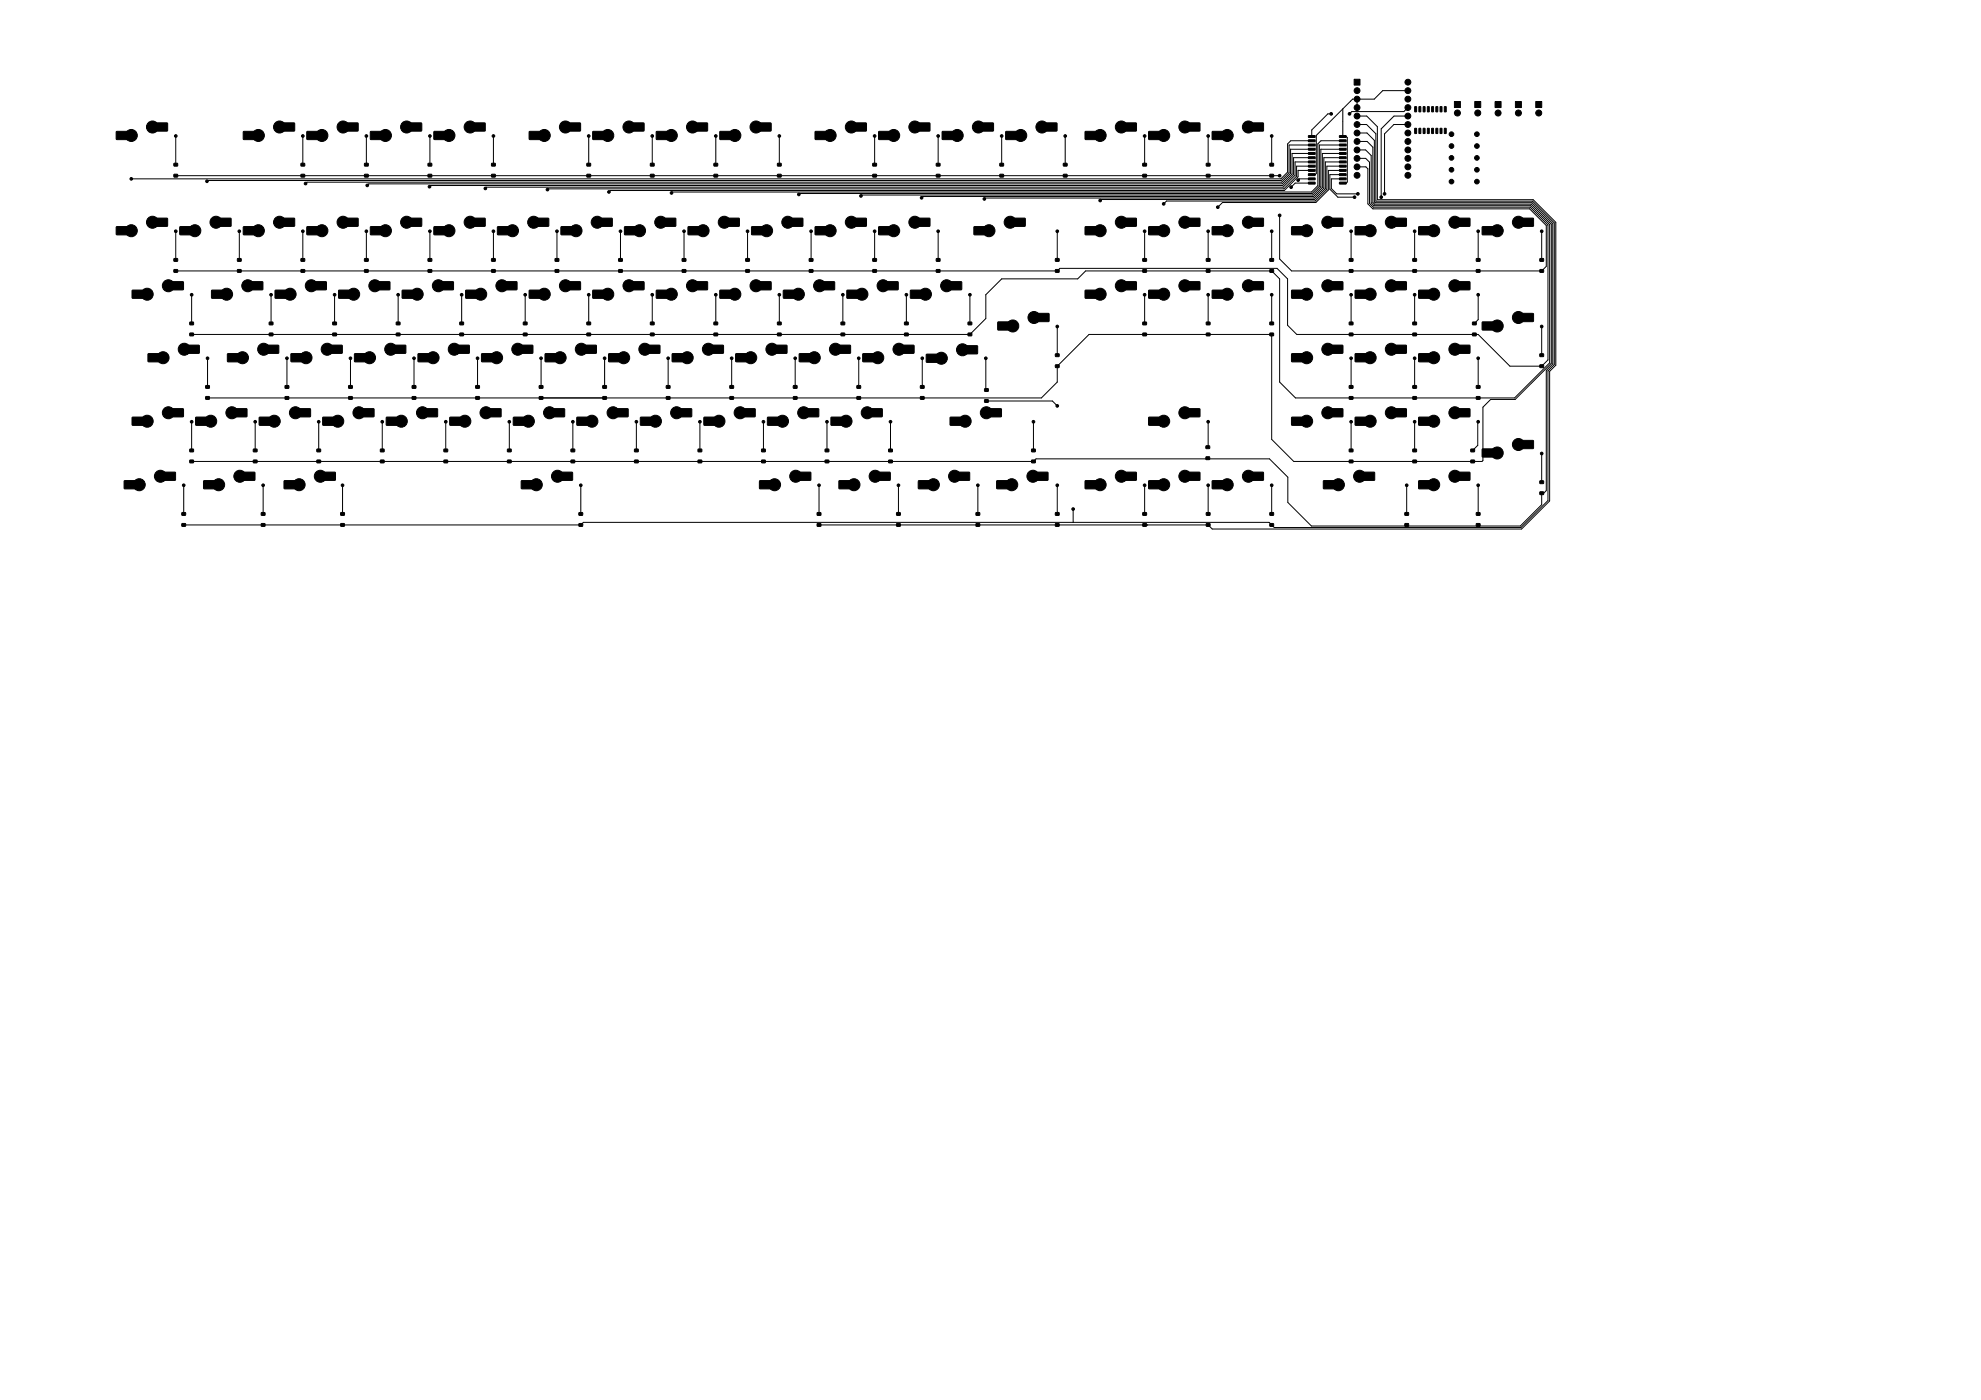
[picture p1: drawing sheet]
<svg xmlns="http://www.w3.org/2000/svg" width="594mm" height="420mm" viewBox="0 0 594 420" stroke-linecap="round" stroke-linejoin="round" font-family="sans-serif">
<g fill="#000" stroke="#000" stroke-width=".3">
<path d="M34.9 39.5h3.4v2.3h-3.4zM46.8 36.9h3.4v2.4h-3.4zM73 39.5h3.4v2.3h-3.4zM84.9 36.9h3.4v2.4h-3.4zM92 39.5h3.4v2.3h-3.4zM103.9 36.9h3.5v2.4h-3.5zM111.1 39.5h3.4v2.3h-3.4zM123 36.9h3.4v2.4h-3.4zM130.1 39.5h3.4v2.3h-3.4zM142 36.9h3.5v2.4h-3.5zM158.7 39.5h3.4v2.3h-3.4zM170.6 36.9h3.4v2.4h-3.4z"/>
<path d="M177.8 39.5h3.4v2.3h-3.4zM189.7 36.9h3.4v2.4h-3.4zM196.8 39.5h3.4v2.3h-3.4zM208.7 36.9h3.4v2.4h-3.4zM215.9 39.5h3.4v2.3h-3.4zM227.8 36.9h3.4v2.4h-3.4zM244.4 39.5h3.4v2.3h-3.4zM256.3 36.9h3.4l.1 2.3-3.4 .1zM263.5 39.5l3.3-.1 .2 2.3-3.4 .2zM275.4 36.9h3.3l.2 2.3-3.4 .1zM282.5 39.5l3.4-.1 .1 2.3-3.4 .2zM294.4 36.9h3.4l.1 2.3-3.4 .1z"/>
<path d="M301.6 39.5l3.3-.1 .2 2.3-3.4 .2zM313.5 36.9h3.3l.2 2.3-3.4 .1zM325.4 39.5l3.3-.1 .2 2.3-3.4 .2zM337.3 36.9h3.3l.2 2.3-3.4 .1zM344.5 39.5l3.3-.1 .1 2.3-3.4 .2zM356.4 36.9h3.3l.1 2.3-3.4 .1zM363.5 39.5l3.3-.1 .2 2.3-3.4 .2zM375.4 36.9h3.3l.2 2.3-3.4 .1zM406 23.8h1.8v1.7h-1.8zM424.2 32l.6 .1-.1 1.5-.5-.1zM424.2 38.5l.6 .1-.1 1.5-.5-.1zM425.5 32l.5 .1v1.5l-.5-.1z"/>
<path d="M425.5 38.5l.5 .1v1.5l-.5-.1zM426.8 32l.5 .1-.1 1.5-.5-.1zM426.8 38.5l.5 .1-.1 1.5-.5-.1zM428 32l.6 .1-.1 1.5-.5-.1zM428 38.5l.6 .1-.1 1.5-.5-.1zM429.3 32l.5 .1v1.5l-.5-.1zM429.3 38.5l.5 .1v1.5l-.5-.1zM430.6 32l.5 .1-.1 1.5-.5-.1zM430.6 38.5l.5 .1-.1 1.5-.5-.1zM431.8 32l.6 .1-.1 1.5-.5-.1zM431.8 38.5l.6 .1-.1 1.5-.5-.1zM433.1 32l.6 .1-.1 1.5-.5-.1z"/>
<path d="M433.1 38.5l.6 .1-.1 1.5-.5-.1zM436.1 30.5h1.8v1.8h-1.8zM442.2 30.5h1.8v1.8h-1.8zM448.3 30.5h1.8v1.8h-1.8zM454.4 30.5h1.8v1.8h-1.8zM460.5 30.5h1.8v1.8h-1.8zM52.2 52.3h1v.8h-1zM52.2 49h1v.8h-1zM90.3 52.3h1v.8h-1zM90.3 49h1v.8h-1zM109.3 52.3h1.1v.8h-1.1zM109.3 49h1.1v.8h-1.1z"/>
<path d="M128.4 52.3h1v.8h-1zM128.4 49h1v.8h-1zM147.4 52.3h1.1v.8h-1.1zM147.4 49h1.1v.8h-1.1zM176 52.3h1.1v.8h-1.1zM176 49h1.1v.8h-1.1zM195 52.3h1.1v.8h-1.1zM195 49h1.1v.8h-1.1zM214.1 52.3h1.1v.8h-1.1zM214.1 49h1.1v.8h-1.1zM233.1 52.3h1.1v.8h-1.1zM233.1 49h1.1v.8h-1.1z"/>
<path d="M261.7 52.3h1.1v.8h-1.1zM261.7 49h1.1v.8h-1.1zM280.8 52.3h1v.8h-1zM280.8 49h1v.8h-1zM299.8 52.3h1.1v.8h-1.1zM299.8 49h1.1v.8h-1.1zM318.9 52.3h1v.8h-1zM318.9 49h1v.8h-1zM342.7 52.3h1.1v.8h-1.1zM342.7 49h1.1v.8h-1.1zM361.7 52.3h1.1v.8h-1.1zM361.7 49h1.1v.8h-1.1z"/>
<path d="M380.8 52.3h1.1v.8h-1.1zM380.8 49h1.1v.8h-1.1zM392.4 54.7l1.9-.1 .1 .5-2 .1zM392.4 53.4h1.9l.1 .5h-2zM392.4 52.1h1.9l.1 .5-2 .1zM392.4 50.9l1.9-.1 .1 .5-2 .1zM392.4 49.6h1.9l.1 .5h-2zM392.4 48.3h1.9l.1 .5-2 .1zM392.4 47.1l1.9-.1 .1 .5-2 .1zM392.4 45.8l1.9-.1 .1 .5-2 .1zM392.4 44.5h1.9l.1 .5-2 .1zM392.4 43.2h1.9l.1 .5-2 .1z"/>
<path d="M392.4 42l1.9-.1 .1 .5-2 .1zM392.4 40.7h1.9l.1 .5h-2zM401.7 40.7h1.9v.5h-1.9zM401.7 42l1.9-.1v.5l-1.9 .1zM401.7 43.2h1.9v.5l-1.9 .1zM401.7 44.5h1.9v.5l-1.9 .1zM401.7 45.8l1.9-.1v.5l-1.9 .1zM401.7 47.1l1.9-.1v.5l-1.9 .1zM401.7 48.3h1.9v.5l-1.9 .1zM401.7 49.6h1.9v.5h-1.9zM401.7 50.9l1.9-.1v.5l-1.9 .1zM401.7 52.1h1.9v.5l-1.9 .1z"/>
<path d="M401.7 53.4h1.9v.5h-1.9zM401.7 54.7l1.9-.1v.5l-1.9 .1zM34.9 68h3.4v2.4h-3.4zM46.8 65.5h3.4v2.4h-3.4zM52.2 77.6h1v.8h-1zM53.9 68h3.4v2.4h-3.4zM65.8 65.5h3.5v2.4h-3.5zM71.2 77.6h1.1v.8h-1.1zM73 68h3.4v2.4h-3.4zM84.9 65.5h3.4v2.4h-3.4zM90.3 77.6h1v.8h-1zM92 68h3.4v2.4h-3.4z"/>
<path d="M103.9 65.5h3.5v2.4h-3.5zM109.3 77.6h1.1v.8h-1.1zM111.1 68h3.4v2.4h-3.4zM123 65.5h3.4v2.4h-3.4zM128.4 77.6h1v.8h-1zM130.1 68h3.4v2.4h-3.4zM142 65.5h3.5v2.4h-3.5zM147.4 77.6h1.1v.8h-1.1zM149.2 68h3.4v2.4h-3.4zM161.1 65.5h3.4v2.4h-3.4zM166.5 77.6h1v.8h-1zM168.2 68h3.4v2.4h-3.4z"/>
<path d="M180.1 65.5h3.5v2.4h-3.5zM185.5 77.6h1.1v.8h-1.1zM187.3 68h3.4v2.4h-3.4zM199.2 65.5h3.4v2.4h-3.4zM204.6 77.6h1v.8h-1zM206.3 68h3.4v2.4h-3.4zM218.2 65.5h3.5v2.4h-3.5zM223.6 77.6h1.1v.8h-1.1zM225.4 68h3.4v2.4h-3.4zM237.3 65.5h3.4v2.4h-3.4zM242.7 77.6h1v.8h-1zM244.4 68h3.4v2.4h-3.4z"/>
<path d="M256.3 65.5l3.4-.1 .1 2.4-3.4 .1zM261.7 77.6h1.1v.8h-1.1zM263.5 68h3.3l.2 2.3-3.4 .1zM275.4 65.5l3.3-.1 .2 2.4-3.4 .1zM280.8 77.6h1v.8h-1zM292.1 68h3.3l.1 2.3-3.4 .1zM304 65.5l3.3-.1 .1 2.4-3.3 .1zM316.5 77.6h1.1v.8h-1.1zM325.4 68h3.3l.2 2.3-3.4 .1zM337.3 65.5l3.3-.1 .2 2.4-3.4 .1zM342.7 77.6h1.1v.8h-1.1zM344.5 68h3.3l.1 2.3-3.4 .1z"/>
<path d="M356.4 65.5l3.3-.1 .1 2.4-3.4 .1zM361.7 77.6h1.1v.8h-1.1zM363.5 68h3.3l.2 2.3-3.4 .1zM375.4 65.5l3.3-.1 .2 2.4-3.4 .1zM380.8 77.6h1.1v.8h-1.1zM387.3 68h3.3l.2 2.3-3.4 .1zM399.2 65.5l3.3-.1 .2 2.4-3.4 .1zM404.6 77.6h1.1v.8h-1.1zM406.4 68h3.3l.1 2.3-3.4 .1zM418.3 65.5l3.3-.1 .1 2.4-3.3 .1zM423.6 77.6h1.1v.8h-1.1zM425.4 68h3.3l.2 2.3-3.4 .1z"/>
<path d="M437.3 65.5l3.3-.1 .2 2.4-3.4 .1zM442.7 77.6h1.1v.8h-1.1zM444.5 68h3.3l.1 2.3-3.4 .1zM456.4 65.5l3.3-.1 .1 2.4-3.3 .1zM461.7 77.6h1.1v.8h-1.1zM39.7 87.1h3.4v2.3h-3.4zM51.6 84.5h3.4v2.4h-3.4zM52.2 80.9h1v.8h-1zM56.9 96.6h1.1v.8h-1.1zM63.5 87.1h3.4v2.3h-3.4zM71.2 80.9h1.1v.8h-1.1zM75.4 84.5h3.4v2.4h-3.4z"/>
<path d="M80.7 96.6h1.1v.8h-1.1zM82.5 87.1h3.4v2.3h-3.4zM90.3 80.9h1v.8h-1zM94.4 84.5h3.4v2.4h-3.4zM99.8 96.6h1.1v.8h-1.1zM101.6 87.1h3.4v2.3h-3.4zM109.3 80.9h1.1v.8h-1.1zM113.5 84.5h3.4v2.4h-3.4zM118.8 96.6h1.1v.8h-1.1zM120.6 87.1h3.4v2.3h-3.4zM128.4 80.9h1v.8h-1zM132.5 84.5h3.4v2.4h-3.4z"/>
<path d="M137.9 96.6h1.1v.8h-1.1zM139.7 87.1h3.4v2.3h-3.4zM147.4 80.9h1.1v.8h-1.1zM151.6 84.5h3.4v2.4h-3.4zM156.9 96.6h1.1v.8h-1.1zM158.7 87.1h3.4v2.3h-3.4zM166.5 80.9h1v.8h-1zM170.6 84.5h3.4v2.4h-3.4zM176 96.6h1.1v.8h-1.1zM177.8 87.1h3.4v2.3h-3.4zM185.5 80.9h1.1v.8h-1.1zM189.7 84.5h3.4v2.4h-3.4z"/>
<path d="M195 96.6h1.1v.8h-1.1zM196.8 87.1h3.4v2.3h-3.4zM204.6 80.9h1v.8h-1zM208.7 84.5h3.4v2.4h-3.4zM214.1 96.6h1.1v.8h-1.1zM215.9 87.1h3.4v2.3h-3.4zM223.6 80.9h1.1v.8h-1.1zM227.8 84.5h3.4v2.4h-3.4zM233.1 96.6h1.1v.8h-1.1zM234.9 87.1h3.4v2.3h-3.4zM242.7 80.9h1v.8h-1zM246.8 84.5h3.4v2.4h-3.4z"/>
<path d="M252.2 96.6h1.1v.8h-1.1zM254 87.1l3.3-.1 .1 2.4-3.4 .1zM261.7 80.9h1.1v.8h-1.1zM265.9 84.5h3.3l.1 2.3-3.3 .2zM271.2 96.6h1.1v.8h-1.1zM273 87.1l3.3-.1 .2 2.4-3.4 .1zM280.8 80.9h1v.8h-1zM284.9 84.5h3.3l.2 2.3-3.4 .2zM290.3 96.6h1.1v.8h-1.1zM299.2 96.6h3.4v2.4h-3.4zM311.1 94.1h3.4v2.3h-3.4zM316.5 80.9h1.1v.8h-1.1z"/>
<path d="M325.4 87.1l3.3-.1 .2 2.4-3.4 .1zM337.3 84.5h3.3l.2 2.3-3.4 .2zM342.7 80.9h1.1v.8h-1.1zM342.7 96.6h1.1v.8h-1.1zM344.5 87.1l3.3-.1 .1 2.4-3.4 .1zM356.4 84.5h3.3l.1 2.3-3.4 .2zM361.7 80.9h1.1v.8h-1.1zM361.7 96.6h1.1v.8h-1.1zM363.5 87.1l3.3-.1 .2 2.4-3.4 .1zM375.4 84.5h3.3l.2 2.3-3.4 .2zM380.8 80.9h1.1v.8h-1.1zM380.8 96.6h1.1v.8h-1.1z"/>
<path d="M387.3 87.1l3.3-.1 .2 2.4-3.4 .1zM399.2 84.5h3.3l.2 2.3-3.4 .2zM404.6 96.6h1.1v.8h-1.1zM404.6 80.9h1.1v.8h-1.1zM406.4 87.1l3.3-.1 .1 2.4-3.4 .1zM418.3 84.5h3.3l.1 2.3-3.3 .2zM423.6 80.9h1.1v.8h-1.1zM423.6 96.6h1.1v.8h-1.1zM425.4 87.1l3.3-.1 .2 2.4-3.4 .1zM437.3 84.5h3.3l.2 2.3-3.4 .2zM441.6 96.6h1v.8h-1zM442.7 80.9h1.1v.8h-1.1z"/>
<path d="M444.5 96.6h3.3l.1 2.3-3.4 .1zM456.4 94.1l3.3-.1 .1 2.3-3.3 .2zM461.7 80.9h1.1v.8h-1.1zM44.4 106.1h3.4v2.4h-3.4zM56.3 103.6h3.4v2.4h-3.4zM56.9 99.9h1.1v.8h-1.1zM61.7 119h1.1v.8h-1.1zM61.7 115.7h1.1v.8h-1.1zM68.2 106.1h3.4v2.4h-3.4zM80.1 103.6h3.4v2.4h-3.4zM80.7 99.9h1.1v.8h-1.1zM85.5 119h1.1v.8h-1.1z"/>
<path d="M85.5 115.7h1.1v.8h-1.1zM87.3 106.1h3.4v2.4h-3.4zM99.2 103.6h3.4v2.4h-3.4zM99.8 99.9h1.1v.8h-1.1zM104.6 119h1v.8h-1zM104.6 115.7h1v.8h-1zM106.3 106.1h3.4v2.4h-3.4zM118.2 103.6h3.4v2.4h-3.4zM118.8 99.9h1.1v.8h-1.1zM123.6 119h1.1v.8h-1.1zM123.6 115.7h1.1v.8h-1.1zM125.4 106.1h3.4v2.4h-3.4z"/>
<path d="M137.3 103.6h3.4v2.4h-3.4zM137.9 99.9h1.1v.8h-1.1zM142.7 119h1v.8h-1zM142.7 115.7h1v.8h-1zM144.4 106.1h3.4v2.4h-3.4zM156.3 103.6h3.4v2.4h-3.4zM156.9 99.9h1.1v.8h-1.1zM161.7 119h1.1v.8h-1.1zM161.7 115.7h1.1v.8h-1.1zM163.5 106.1h3.4v2.4h-3.4zM175.4 103.6h3.4v2.4h-3.4zM176 99.9h1.1v.8h-1.1z"/>
<path d="M180.8 119h1v.8h-1zM180.8 115.7h1v.8h-1zM182.5 106.1h3.4v2.4h-3.4zM194.4 103.6h3.4v2.4h-3.4zM195 99.9h1.1v.8h-1.1zM199.8 119h1.1v.8h-1.1zM199.8 115.7h1.1v.8h-1.1zM201.6 106.1h3.4v2.4h-3.4zM213.5 103.6h3.4v2.4h-3.4zM214.1 99.9h1.1v.8h-1.1zM218.9 119h1v.8h-1zM218.9 115.7h1v.8h-1z"/>
<path d="M220.6 106.1h3.4v2.4h-3.4zM232.5 103.6h3.4v2.4h-3.4zM233.1 99.9h1.1v.8h-1.1zM237.9 119h1.1v.8h-1.1zM237.9 115.7h1.1v.8h-1.1zM239.7 106.1h3.4v2.4h-3.4zM251.6 103.6l3.3-.1 .1 2.4-3.3 .1zM252.2 99.9h1.1v.8h-1.1zM257 119h1v.8h-1zM257 115.7h1v.8h-1zM258.7 106.1h3.4l.1 2.3-3.4 .1zM270.6 103.6l3.4-.1 .1 2.4-3.4 .1z"/>
<path d="M271.2 99.9h1.1v.8h-1.1zM276 119h1.1v.8h-1.1zM276 115.7h1.1v.8h-1.1zM277.8 106.3l3.3-.1 .1 2.4-3.4 .1zM289.7 103.8l3.3-.1 .1 2.3-3.4 .1zM290.3 99.9h1.1v.8h-1.1zM295.2 116.6h1.1v.8h-1.1zM316.5 109.5h1.1v.7h-1.1zM316.5 106.2h1.1v.7h-1.1zM342.7 99.9h1.1v.8h-1.1zM361.7 99.9h1.1v.8h-1.1zM380.8 99.9h1.1v.8h-1.1z"/>
<path d="M387.3 106.1h3.3l.2 2.3-3.4 .1zM399.2 103.6l3.3-.1 .2 2.4-3.4 .1zM404.6 99.9h1.1v.8h-1.1zM404.6 119h1.1v.8h-1.1zM404.6 115.7h1.1v.8h-1.1zM406.4 106.1h3.3l.1 2.3-3.4 .1zM418.3 103.6l3.3-.1 .1 2.4-3.3 .1zM423.6 119h1.1v.8h-1.1zM423.6 115.7h1.1v.8h-1.1zM423.6 99.9h1.1v.8h-1.1zM425.4 106.1h3.3l.2 2.3-3.4 .1zM437.3 103.6l3.3-.1 .2 2.4-3.4 .1z"/>
<path d="M441.6 99.9h1v.8h-1zM442.7 119h1.1v.8h-1.1zM442.7 115.7h1.1v.8h-1.1zM461.7 109.5h1.1v.7h-1.1zM461.7 106.2h1.1v.7h-1.1zM39.7 125.2h3.4v2.3h-3.4zM51.6 122.6h3.4v2.4h-3.4zM56.9 138h1.1v.8h-1.1zM56.9 134.7h1.1v.8h-1.1zM58.7 125.2h3.4v2.3h-3.4zM70.6 122.6h3.4v2.4h-3.4zM76 138h1.1v.8h-1.1z"/>
<path d="M76 134.7h1.1v.8h-1.1zM77.8 125.2h3.4v2.3h-3.4zM89.7 122.6h3.4v2.4h-3.4zM95 138h1.1v.8h-1.1zM95 134.7h1.1v.8h-1.1zM96.8 125.2h3.4v2.3h-3.4zM108.7 122.6h3.4v2.4h-3.4zM114.1 138h1.1v.8h-1.1zM114.1 134.7h1.1v.8h-1.1zM115.9 125.2h3.4v2.3h-3.4zM127.8 122.6h3.4v2.4h-3.4zM133.1 138h1.1v.8h-1.1z"/>
<path d="M133.1 134.7h1.1v.8h-1.1zM134.9 125.2h3.4v2.3h-3.4zM146.8 122.6h3.4v2.4h-3.4zM152.2 138h1.1v.8h-1.1zM152.2 134.7h1.1v.8h-1.1zM154 125.2h3.4v2.3h-3.4zM165.9 122.6h3.4v2.4h-3.4zM171.2 138h1.1v.8h-1.1zM171.2 134.7h1.1v.8h-1.1zM173 125.2h3.4v2.3h-3.4zM184.9 122.6h3.4v2.4h-3.4zM190.3 138h1.1v.8h-1.1z"/>
<path d="M190.3 134.7h1.1v.8h-1.1zM192.1 125.2h3.4v2.3h-3.4zM204 122.6h3.4v2.4h-3.4zM209.3 138h1.1v.8h-1.1zM209.3 134.7h1.1v.8h-1.1zM211.1 125.2h3.4v2.3h-3.4zM223 122.6h3.4v2.4h-3.4zM228.4 138h1.1v.8h-1.1zM228.4 134.7h1.1v.8h-1.1zM230.2 125.2h3.4v2.3h-3.4zM242.1 122.6h3.4v2.4h-3.4zM247.4 138h1.1v.8h-1.1z"/>
<path d="M247.4 134.7h1.1v.8h-1.1zM249.2 125.2h3.4v2.3h-3.4zM261.1 122.6h3.3l.2 2.3-3.4 .2zM266.5 138h1.1v.8h-1.1zM266.5 134.7h1.1v.8h-1.1zM284.9 125.2h3.4v2.3h-3.4zM295.2 119.9h1.1v.8h-1.1zM296.8 122.6h3.4v2.4h-3.4zM309.3 138h1.1v.8h-1.1zM309.3 134.7h1.1v.8h-1.1zM344.5 125.2l3.3-.1 .1 2.4-3.4 .1zM356.4 122.6h3.3l.1 2.3-3.4 .2z"/>
<path d="M361.6 137.1l1-.1 .1 .8-1 .1zM361.6 133.8h1.1v.7h-1.1zM387.3 125.2l3.3-.1 .2 2.4-3.4 .1zM399.2 122.6h3.3l.2 2.3-3.4 .2zM404.6 138h1.1v.8h-1.1zM404.6 134.7h1.1v.8h-1.1zM406.4 125.2l3.3-.1 .1 2.4-3.4 .1zM418.3 122.6h3.3l.1 2.3-3.3 .2zM423.6 138h1.1v.8h-1.1zM423.6 134.7h1.1v.8h-1.1zM425.4 125.2l3.3-.1 .2 2.4-3.4 .1zM437.3 122.6h3.3l.2 2.3-3.4 .2z"/>
<path d="M441 138h1.1v.8h-1.1zM441 134.7h1.1v.8h-1.1zM444.5 134.7h3.3l.1 2.3-3.4 .1zM456.4 132.2l3.3-.1 .1 2.3-3.3 .2zM37.3 144.2h3.4v2.4h-3.4zM49.2 141.7h3.4v2.4h-3.4zM54.6 157.1h1v.8h-1zM54.6 153.8h1v.8h-1zM61.1 144.2h3.4v2.4h-3.4zM73 141.7h3.4v2.4h-3.4zM78.4 157.1h1v.8h-1zM78.4 153.8h1v.8h-1z"/>
<path d="M85.2 144.2h3.4v2.4h-3.4zM97.1 141.7h3.4v2.4h-3.4zM102.2 157.1h1v.8h-1zM102.2 153.8h1v.8h-1zM156.3 144.2h3.4v2.4h-3.4zM168.2 141.7h3.4v2.4h-3.4zM173.6 157.1h1.1v.8h-1.1zM173.6 153.8h1.1v.8h-1.1zM227.8 144.2h3.4v2.4h-3.4zM239.7 141.7h3.4v2.4h-3.4zM245.1 157.1h1v.8h-1zM245.1 153.8h1v.8h-1z"/>
<path d="M251.6 144.2h3.4v2.4h-3.4zM263.5 141.7h3.4v2.4h-3.4zM268.9 157.1h1v.8h-1zM268.9 153.8h1v.8h-1zM275.4 144.2h3.4v2.4h-3.4zM287.3 141.7h3.4v2.4h-3.4zM292.7 157.1h1v.8h-1zM292.7 153.8h1v.8h-1zM298.9 144.2h3.4v2.4h-3.4zM310.8 141.7h3.4v2.4h-3.4zM316.5 157.1h1.1v.8h-1.1zM316.5 153.8h1.1v.8h-1.1z"/>
<path d="M325.4 144.2h3.3l.2 2.3-3.4 .1zM337.3 141.7l3.3-.1 .2 2.4-3.4 .1zM342.7 157.1h1.1v.8h-1.1zM342.7 153.8h1.1v.8h-1.1zM344.5 144.2h3.3l.1 2.3-3.4 .1zM356.4 141.7l3.3-.1 .1 2.4-3.4 .1zM361.7 157.1h1.1v.8h-1.1zM361.7 153.8h1.1v.8h-1.1zM363.5 144.2h3.3l.2 2.3-3.4 .1zM375.4 141.7l3.3-.1 .2 2.4-3.4 .1zM380.8 157.1h1.1v.8h-1.1zM380.8 153.8h1.1v.8h-1.1z"/>
<path d="M396.8 144.2h3.4l.1 2.3-3.4 .1zM408.7 141.7l3.4-.1 .1 2.4-3.4 .1zM421.3 157.1h1v.8h-1zM421.3 153.8h1v.8h-1zM425.4 144.2h3.3l.2 2.3-3.4 .1zM437.3 141.7l3.3-.1 .2 2.4-3.4 .1zM442.7 157.1h1.1v.8h-1.1zM442.7 153.8h1.1v.8h-1.1zM461.7 147.6h1.1v.7h-1.1zM461.7 144.3h1.1v.7h-1.1z"/>
<circle cx="45.7" cy="38.1" r="1.8"/>
<circle cx="83.8" cy="38.1" r="1.8"/>
<circle cx="102.9" cy="38.1" r="1.8"/>
<circle cx="121.9" cy="38.1" r="1.8"/>
<circle cx="141" cy="38.1" r="1.8"/>
<circle cx="169.5" cy="38.1" r="1.8"/>
<circle cx="188.6" cy="38.1" r="1.8"/>
<circle cx="207.6" cy="38.1" r="1.8"/>
<circle cx="226.7" cy="38.1" r="1.8"/>
<circle cx="255.3" cy="38.1" r="1.8"/>
<circle cx="274.3" cy="38.1" r="1.8"/>
<circle cx="293.4" cy="38.1" r="1.8"/>
<circle cx="312.4" cy="38.1" r="1.8"/>
<circle cx="336.2" cy="38.1" r="1.8"/>
<circle cx="355.3" cy="38.1" r="1.8"/>
<circle cx="374.3" cy="38.1" r="1.8"/>
<circle cx="399.2" cy="34.2" r=".4"/>
<circle cx="404.7" cy="34.2" r=".4"/>
<circle cx="406.9" cy="39.9" r=".88"/>
<circle cx="406.9" cy="34.8" r=".88"/>
<circle cx="406.9" cy="27.2" r=".88"/>
<circle cx="406.9" cy="29.7" r=".88"/>
<circle cx="406.9" cy="32.3" r=".88"/>
<circle cx="406.9" cy="37.4" r=".88"/>
<circle cx="422.2" cy="32.3" r=".88"/>
<circle cx="422.2" cy="27.2" r=".88"/>
<circle cx="422.2" cy="39.9" r=".88"/>
<circle cx="422.2" cy="37.4" r=".88"/>
<circle cx="422.2" cy="24.7" r=".88"/>
<circle cx="422.2" cy="34.8" r=".88"/>
<circle cx="422.2" cy="29.7" r=".88"/>
<circle cx="437" cy="33.9" r=".9"/>
<circle cx="443.1" cy="33.9" r=".9"/>
<circle cx="449.2" cy="33.9" r=".9"/>
<circle cx="455.3" cy="33.9" r=".9"/>
<circle cx="461.4" cy="33.9" r=".9"/>
<circle cx="39.4" cy="53.7" r=".4"/>
<circle cx="39.4" cy="40.6" r="1.8"/>
<circle cx="52.7" cy="40.8" r=".4"/>
<circle cx="62.1" cy="54.4" r=".4"/>
<circle cx="77.5" cy="40.6" r="1.8"/>
<circle cx="90.8" cy="40.8" r=".4"/>
<circle cx="91.6" cy="55.1" r=".4"/>
<circle cx="96.5" cy="40.6" r="1.8"/>
<circle cx="109.9" cy="40.8" r=".4"/>
<circle cx="110.1" cy="55.6" r=".4"/>
<circle cx="115.6" cy="40.6" r="1.8"/>
<circle cx="128.8" cy="56" r=".4"/>
<circle cx="128.9" cy="40.8" r=".4"/>
<circle cx="134.6" cy="40.6" r="1.8"/>
<circle cx="145.5" cy="56.5" r=".4"/>
<circle cx="148" cy="40.8" r=".4"/>
<circle cx="163.2" cy="40.6" r="1.8"/>
<circle cx="164.2" cy="56.9" r=".4"/>
<circle cx="176.5" cy="40.8" r=".4"/>
<circle cx="182.2" cy="40.6" r="1.8"/>
<circle cx="182.6" cy="57.6" r=".4"/>
<circle cx="195.6" cy="40.8" r=".4"/>
<circle cx="201.3" cy="40.6" r="1.8"/>
<circle cx="201.4" cy="57.9" r=".4"/>
<circle cx="214.6" cy="40.8" r=".4"/>
<circle cx="220.3" cy="40.6" r="1.8"/>
<circle cx="233.7" cy="40.8" r=".4"/>
<circle cx="239.5" cy="58.3" r=".4"/>
<circle cx="248.9" cy="40.6" r="1.8"/>
<circle cx="258.2" cy="58.8" r=".4"/>
<circle cx="262.3" cy="40.8" r=".4"/>
<circle cx="268" cy="40.6" r="1.8"/>
<circle cx="276.3" cy="59.3" r=".4"/>
<circle cx="281.3" cy="40.8" r=".4"/>
<circle cx="287" cy="40.6" r="1.8"/>
<circle cx="295.2" cy="59.7" r=".4"/>
<circle cx="300.4" cy="40.8" r=".4"/>
<circle cx="306.1" cy="40.6" r="1.8"/>
<circle cx="319.4" cy="40.8" r=".4"/>
<circle cx="329.9" cy="40.6" r="1.8"/>
<circle cx="343.2" cy="40.8" r=".4"/>
<circle cx="348.9" cy="40.6" r="1.8"/>
<circle cx="362.3" cy="40.8" r=".4"/>
<circle cx="368" cy="40.6" r="1.8"/>
<circle cx="381.3" cy="40.8" r=".4"/>
<circle cx="383.7" cy="52.7" r=".4"/>
<circle cx="387.1" cy="56.1" r=".4"/>
<circle cx="389.2" cy="54" r=".4"/>
<circle cx="406.2" cy="59.2" r=".4"/>
<circle cx="406.9" cy="45" r=".88"/>
<circle cx="406.9" cy="50.1" r=".88"/>
<circle cx="406.9" cy="47.5" r=".88"/>
<circle cx="406.9" cy="52.6" r=".88"/>
<circle cx="406.9" cy="42.4" r=".88"/>
<circle cx="407.2" cy="58.2" r=".4"/>
<circle cx="414.2" cy="59.2" r=".4"/>
<circle cx="415.2" cy="58.2" r=".4"/>
<circle cx="422.2" cy="42.4" r=".88"/>
<circle cx="422.2" cy="52.6" r=".88"/>
<circle cx="422.2" cy="47.5" r=".88"/>
<circle cx="422.2" cy="50.1" r=".88"/>
<circle cx="422.2" cy="45" r=".88"/>
<circle cx="435.2" cy="43.8" r=".7"/>
<circle cx="435.2" cy="54.5" r=".7"/>
<circle cx="435.2" cy="40.3" r=".7"/>
<circle cx="435.2" cy="50.9" r=".7"/>
<circle cx="435.2" cy="47.4" r=".7"/>
<circle cx="442.8" cy="50.9" r=".7"/>
<circle cx="442.8" cy="54.5" r=".7"/>
<circle cx="442.8" cy="40.3" r=".7"/>
<circle cx="442.8" cy="47.4" r=".7"/>
<circle cx="442.8" cy="43.8" r=".7"/>
<circle cx="39.4" cy="69.2" r="1.8"/>
<circle cx="45.7" cy="66.7" r="1.8"/>
<circle cx="52.7" cy="69.4" r=".4"/>
<circle cx="58.4" cy="69.2" r="1.8"/>
<circle cx="64.8" cy="66.7" r="1.8"/>
<circle cx="71.8" cy="69.4" r=".4"/>
<circle cx="77.5" cy="69.2" r="1.8"/>
<circle cx="83.8" cy="66.7" r="1.8"/>
<circle cx="90.8" cy="69.4" r=".4"/>
<circle cx="96.5" cy="69.2" r="1.8"/>
<circle cx="102.9" cy="66.7" r="1.8"/>
<circle cx="109.9" cy="69.4" r=".4"/>
<circle cx="115.6" cy="69.2" r="1.8"/>
<circle cx="121.9" cy="66.7" r="1.8"/>
<circle cx="128.9" cy="69.4" r=".4"/>
<circle cx="134.6" cy="69.2" r="1.8"/>
<circle cx="141" cy="66.7" r="1.8"/>
<circle cx="148" cy="69.4" r=".4"/>
<circle cx="153.7" cy="69.2" r="1.8"/>
<circle cx="160" cy="66.7" r="1.8"/>
<circle cx="167" cy="69.4" r=".4"/>
<circle cx="172.7" cy="69.2" r="1.8"/>
<circle cx="179.1" cy="66.7" r="1.8"/>
<circle cx="186.1" cy="69.4" r=".4"/>
<circle cx="191.8" cy="69.2" r="1.8"/>
<circle cx="198.1" cy="66.7" r="1.8"/>
<circle cx="205.1" cy="69.4" r=".4"/>
<circle cx="210.8" cy="69.2" r="1.8"/>
<circle cx="217.2" cy="66.7" r="1.8"/>
<circle cx="224.2" cy="69.4" r=".4"/>
<circle cx="229.9" cy="69.2" r="1.8"/>
<circle cx="236.2" cy="66.7" r="1.8"/>
<circle cx="243.2" cy="69.4" r=".4"/>
<circle cx="248.9" cy="69.2" r="1.8"/>
<circle cx="255.3" cy="66.7" r="1.8"/>
<circle cx="262.3" cy="69.4" r=".4"/>
<circle cx="268" cy="69.2" r="1.8"/>
<circle cx="274.3" cy="66.7" r="1.8"/>
<circle cx="281.3" cy="69.4" r=".4"/>
<circle cx="296.5" cy="69.2" r="1.8"/>
<circle cx="302.9" cy="66.7" r="1.8"/>
<circle cx="317" cy="69.4" r=".4"/>
<circle cx="329.9" cy="69.2" r="1.8"/>
<circle cx="329.9" cy="60.2" r=".4"/>
<circle cx="336.2" cy="66.7" r="1.8"/>
<circle cx="343.2" cy="69.4" r=".4"/>
<circle cx="348.9" cy="69.2" r="1.8"/>
<circle cx="348.9" cy="61.2" r=".4"/>
<circle cx="355.3" cy="66.7" r="1.8"/>
<circle cx="362.3" cy="69.4" r=".4"/>
<circle cx="365.2" cy="62.2" r=".4"/>
<circle cx="368" cy="69.2" r="1.8"/>
<circle cx="374.3" cy="66.7" r="1.8"/>
<circle cx="381.3" cy="69.4" r=".4"/>
<circle cx="383.7" cy="64.6" r=".4"/>
<circle cx="391.8" cy="69.2" r="1.8"/>
<circle cx="398.1" cy="66.7" r="1.8"/>
<circle cx="405.1" cy="69.4" r=".4"/>
<circle cx="410.8" cy="69.2" r="1.8"/>
<circle cx="417.2" cy="66.7" r="1.8"/>
<circle cx="424.2" cy="69.4" r=".4"/>
<circle cx="429.9" cy="69.2" r="1.8"/>
<circle cx="436.2" cy="66.7" r="1.8"/>
<circle cx="443.2" cy="69.4" r=".4"/>
<circle cx="448.9" cy="69.2" r="1.8"/>
<circle cx="455.3" cy="66.7" r="1.8"/>
<circle cx="462.3" cy="69.4" r=".4"/>
<circle cx="44.1" cy="88.3" r="1.8"/>
<circle cx="50.5" cy="85.7" r="1.8"/>
<circle cx="57.5" cy="88.4" r=".4"/>
<circle cx="67.9" cy="88.3" r="1.8"/>
<circle cx="74.3" cy="85.7" r="1.8"/>
<circle cx="81.3" cy="88.4" r=".4"/>
<circle cx="87" cy="88.3" r="1.8"/>
<circle cx="93.3" cy="85.7" r="1.8"/>
<circle cx="100.3" cy="88.4" r=".4"/>
<circle cx="106" cy="88.3" r="1.8"/>
<circle cx="112.4" cy="85.7" r="1.8"/>
<circle cx="119.4" cy="88.4" r=".4"/>
<circle cx="125.1" cy="88.3" r="1.8"/>
<circle cx="131.4" cy="85.7" r="1.8"/>
<circle cx="138.4" cy="88.4" r=".4"/>
<circle cx="144.1" cy="88.3" r="1.8"/>
<circle cx="150.5" cy="85.7" r="1.8"/>
<circle cx="157.5" cy="88.4" r=".4"/>
<circle cx="163.2" cy="88.3" r="1.8"/>
<circle cx="169.5" cy="85.7" r="1.8"/>
<circle cx="176.5" cy="88.4" r=".4"/>
<circle cx="182.2" cy="88.3" r="1.8"/>
<circle cx="188.6" cy="85.7" r="1.8"/>
<circle cx="195.6" cy="88.4" r=".4"/>
<circle cx="201.3" cy="88.3" r="1.8"/>
<circle cx="207.6" cy="85.7" r="1.8"/>
<circle cx="214.6" cy="88.4" r=".4"/>
<circle cx="220.3" cy="88.3" r="1.8"/>
<circle cx="226.7" cy="85.7" r="1.8"/>
<circle cx="233.7" cy="88.4" r=".4"/>
<circle cx="239.4" cy="88.3" r="1.8"/>
<circle cx="245.7" cy="85.7" r="1.8"/>
<circle cx="252.7" cy="88.4" r=".4"/>
<circle cx="258.4" cy="88.3" r="1.8"/>
<circle cx="264.8" cy="85.7" r="1.8"/>
<circle cx="271.8" cy="88.4" r=".4"/>
<circle cx="277.5" cy="88.3" r="1.8"/>
<circle cx="283.8" cy="85.7" r="1.8"/>
<circle cx="290.8" cy="88.4" r=".4"/>
<circle cx="303.7" cy="97.8" r="1.8"/>
<circle cx="310" cy="95.3" r="1.8"/>
<circle cx="317" cy="97.9" r=".4"/>
<circle cx="329.9" cy="88.3" r="1.8"/>
<circle cx="336.2" cy="85.7" r="1.8"/>
<circle cx="343.2" cy="88.4" r=".4"/>
<circle cx="348.9" cy="88.3" r="1.8"/>
<circle cx="355.3" cy="85.7" r="1.8"/>
<circle cx="362.3" cy="88.4" r=".4"/>
<circle cx="368" cy="88.3" r="1.8"/>
<circle cx="374.3" cy="85.7" r="1.8"/>
<circle cx="381.3" cy="88.4" r=".4"/>
<circle cx="391.8" cy="88.3" r="1.8"/>
<circle cx="398.1" cy="85.7" r="1.8"/>
<circle cx="405.1" cy="88.4" r=".4"/>
<circle cx="410.8" cy="88.3" r="1.8"/>
<circle cx="417.2" cy="85.7" r="1.8"/>
<circle cx="424.2" cy="88.4" r=".4"/>
<circle cx="429.9" cy="88.3" r="1.8"/>
<circle cx="436.2" cy="85.7" r="1.8"/>
<circle cx="443.2" cy="88.4" r=".4"/>
<circle cx="448.9" cy="97.8" r="1.8"/>
<circle cx="455.3" cy="95.3" r="1.8"/>
<circle cx="462.3" cy="97.9" r=".4"/>
<circle cx="48.9" cy="107.3" r="1.8"/>
<circle cx="55.2" cy="104.8" r="1.8"/>
<circle cx="62.2" cy="107.5" r=".4"/>
<circle cx="72.7" cy="107.3" r="1.8"/>
<circle cx="79.1" cy="104.8" r="1.8"/>
<circle cx="86" cy="107.5" r=".4"/>
<circle cx="91.8" cy="107.3" r="1.8"/>
<circle cx="98.1" cy="104.8" r="1.8"/>
<circle cx="105.1" cy="107.5" r=".4"/>
<circle cx="110.8" cy="107.3" r="1.8"/>
<circle cx="117.2" cy="104.8" r="1.8"/>
<circle cx="124.1" cy="107.5" r=".4"/>
<circle cx="129.9" cy="107.3" r="1.8"/>
<circle cx="136.2" cy="104.8" r="1.8"/>
<circle cx="143.2" cy="107.5" r=".4"/>
<circle cx="148.9" cy="107.3" r="1.8"/>
<circle cx="155.3" cy="104.8" r="1.8"/>
<circle cx="162.2" cy="107.5" r=".4"/>
<circle cx="168" cy="107.3" r="1.8"/>
<circle cx="174.3" cy="104.8" r="1.8"/>
<circle cx="181.3" cy="107.5" r=".4"/>
<circle cx="187" cy="107.3" r="1.8"/>
<circle cx="193.4" cy="104.8" r="1.8"/>
<circle cx="200.3" cy="107.5" r=".4"/>
<circle cx="206.1" cy="107.3" r="1.8"/>
<circle cx="212.4" cy="104.8" r="1.8"/>
<circle cx="219.4" cy="107.5" r=".4"/>
<circle cx="225.1" cy="107.3" r="1.8"/>
<circle cx="231.5" cy="104.8" r="1.8"/>
<circle cx="238.4" cy="107.5" r=".4"/>
<circle cx="244.2" cy="107.3" r="1.8"/>
<circle cx="250.5" cy="104.8" r="1.8"/>
<circle cx="257.5" cy="107.5" r=".4"/>
<circle cx="263.2" cy="107.3" r="1.8"/>
<circle cx="269.6" cy="104.8" r="1.8"/>
<circle cx="276.5" cy="107.5" r=".4"/>
<circle cx="282.3" cy="107.5" r="1.8"/>
<circle cx="288.6" cy="104.9" r="1.8"/>
<circle cx="295.6" cy="107.5" r=".4"/>
<circle cx="391.8" cy="107.3" r="1.8"/>
<circle cx="398.1" cy="104.8" r="1.8"/>
<circle cx="405.1" cy="107.5" r=".4"/>
<circle cx="410.8" cy="107.3" r="1.8"/>
<circle cx="417.2" cy="104.8" r="1.8"/>
<circle cx="424.2" cy="107.5" r=".4"/>
<circle cx="429.9" cy="107.3" r="1.8"/>
<circle cx="436.2" cy="104.8" r="1.8"/>
<circle cx="443.2" cy="107.5" r=".4"/>
<circle cx="44.1" cy="126.4" r="1.8"/>
<circle cx="50.5" cy="123.8" r="1.8"/>
<circle cx="57.5" cy="126.5" r=".4"/>
<circle cx="63.2" cy="126.4" r="1.8"/>
<circle cx="69.5" cy="123.8" r="1.8"/>
<circle cx="76.5" cy="126.5" r=".4"/>
<circle cx="82.2" cy="126.4" r="1.8"/>
<circle cx="88.6" cy="123.8" r="1.8"/>
<circle cx="95.6" cy="126.5" r=".4"/>
<circle cx="101.3" cy="126.4" r="1.8"/>
<circle cx="107.6" cy="123.8" r="1.8"/>
<circle cx="114.6" cy="126.5" r=".4"/>
<circle cx="120.3" cy="126.4" r="1.8"/>
<circle cx="126.7" cy="123.8" r="1.8"/>
<circle cx="133.7" cy="126.5" r=".4"/>
<circle cx="139.4" cy="126.4" r="1.8"/>
<circle cx="145.7" cy="123.8" r="1.8"/>
<circle cx="152.7" cy="126.5" r=".4"/>
<circle cx="158.4" cy="126.4" r="1.8"/>
<circle cx="164.8" cy="123.8" r="1.8"/>
<circle cx="171.8" cy="126.5" r=".4"/>
<circle cx="177.5" cy="126.4" r="1.8"/>
<circle cx="183.8" cy="123.8" r="1.8"/>
<circle cx="190.8" cy="126.5" r=".4"/>
<circle cx="196.5" cy="126.4" r="1.8"/>
<circle cx="202.9" cy="123.8" r="1.8"/>
<circle cx="209.9" cy="126.5" r=".4"/>
<circle cx="215.6" cy="126.4" r="1.8"/>
<circle cx="221.9" cy="123.8" r="1.8"/>
<circle cx="228.9" cy="126.5" r=".4"/>
<circle cx="234.6" cy="126.4" r="1.8"/>
<circle cx="241" cy="123.8" r="1.8"/>
<circle cx="248" cy="126.5" r=".4"/>
<circle cx="253.7" cy="126.4" r="1.8"/>
<circle cx="260" cy="123.8" r="1.8"/>
<circle cx="267" cy="126.5" r=".4"/>
<circle cx="289.4" cy="126.4" r="1.8"/>
<circle cx="295.8" cy="123.8" r="1.8"/>
<circle cx="309.9" cy="126.5" r=".4"/>
<circle cx="317" cy="121.8" r=".4"/>
<circle cx="348.9" cy="126.4" r="1.8"/>
<circle cx="355.3" cy="123.8" r="1.8"/>
<circle cx="362.3" cy="126.5" r=".4"/>
<circle cx="391.8" cy="126.4" r="1.8"/>
<circle cx="398.1" cy="123.8" r="1.8"/>
<circle cx="405.1" cy="126.5" r=".4"/>
<circle cx="410.8" cy="126.4" r="1.8"/>
<circle cx="417.2" cy="123.8" r="1.8"/>
<circle cx="424.2" cy="126.5" r=".4"/>
<circle cx="429.9" cy="126.4" r="1.8"/>
<circle cx="436.2" cy="123.8" r="1.8"/>
<circle cx="443.2" cy="126.5" r=".4"/>
<circle cx="448.9" cy="135.9" r="1.8"/>
<circle cx="455.3" cy="133.4" r="1.8"/>
<circle cx="462.3" cy="136" r=".4"/>
<circle cx="41.8" cy="145.4" r="1.8"/>
<circle cx="48.1" cy="142.9" r="1.8"/>
<circle cx="55.1" cy="145.6" r=".4"/>
<circle cx="65.6" cy="145.4" r="1.8"/>
<circle cx="71.9" cy="142.9" r="1.8"/>
<circle cx="78.9" cy="145.6" r=".4"/>
<circle cx="89.7" cy="145.4" r="1.8"/>
<circle cx="96" cy="142.9" r="1.8"/>
<circle cx="102.7" cy="145.6" r=".4"/>
<circle cx="160.8" cy="145.4" r="1.8"/>
<circle cx="167.2" cy="142.9" r="1.8"/>
<circle cx="174.1" cy="145.6" r=".4"/>
<circle cx="232.3" cy="145.4" r="1.8"/>
<circle cx="238.6" cy="142.9" r="1.8"/>
<circle cx="245.6" cy="145.6" r=".4"/>
<circle cx="256.1" cy="145.4" r="1.8"/>
<circle cx="262.4" cy="142.9" r="1.8"/>
<circle cx="269.4" cy="145.6" r=".4"/>
<circle cx="279.9" cy="145.4" r="1.8"/>
<circle cx="286.2" cy="142.9" r="1.8"/>
<circle cx="293.2" cy="145.6" r=".4"/>
<circle cx="303.4" cy="145.4" r="1.8"/>
<circle cx="309.7" cy="142.9" r="1.8"/>
<circle cx="317" cy="145.6" r=".4"/>
<circle cx="321.8" cy="152.7" r=".4"/>
<circle cx="329.9" cy="145.4" r="1.8"/>
<circle cx="336.2" cy="142.9" r="1.8"/>
<circle cx="343.2" cy="145.6" r=".4"/>
<circle cx="348.9" cy="145.4" r="1.8"/>
<circle cx="355.3" cy="142.9" r="1.8"/>
<circle cx="362.3" cy="145.6" r=".4"/>
<circle cx="368" cy="145.4" r="1.8"/>
<circle cx="374.3" cy="142.9" r="1.8"/>
<circle cx="381.3" cy="145.6" r=".4"/>
<circle cx="401.3" cy="145.4" r="1.8"/>
<circle cx="407.7" cy="142.9" r="1.8"/>
<circle cx="421.8" cy="145.6" r=".4"/>
<circle cx="429.9" cy="145.4" r="1.8"/>
<circle cx="436.2" cy="142.9" r="1.8"/>
<circle cx="443.2" cy="145.6" r=".4"/>
</g>
<g fill="none" stroke="#000" stroke-width=".3">
<path d="M399.2 34.2h-1l-4.9 4.8v2M402.6 32.7v8.3h1.1l.3 .3v13.3l-.3 .3h-1.1M406.9 29.7v2.6M406.9 37.4h2.9l2.8 2.7v20.3h46.9l6.6 6.5v42.5l-1.9 1.9v38.9l-8.1 8.1h-74l-1.6-1.6h-205.6l-.8 .8h-119M406.9 34.8h2.9l3.2 3.2v21.9h46.7l6.8 6.8v42.9l-1.8 1.8v38.9l-8.5 8.4h-92.7l-1.2-1.2h-116.7M406.9 39.9h3l2.2 2.2v18.5l.3 .2h47l6.2 6.3v42.1l-1.9 1.9v36.1l-.8 .8h-.6v3.4l-6.4 6.4h-12.3l-.4-.3-.3 .3h-20.8l-.3-.3-.3 .3h-28.3l-7-7.1v-7.5l-5.5-5.5h-70l-.8 .7h-252.4M407.4 24.1l-.5 .6M422.2 27.2h-7.6l-2.5 2.5h-6.5l-10.9 10.9v11.5l-.3 .3h-1.1M422.2 37.4h-4.2l-2.8 2.8v18M422.2 34.8h-4.2l-3.8 3.9v20.5M422.2 32.3l-1.2 1.2h-15.7l-.6 .7M52.7 52.7h331"/>
<path d="M52.7 40.8v8.6M90.8 40.8v8.6M109.9 40.8v8.6M128.9 40.8v8.6M148 40.8v8.6M176.5 40.8v8.6M195.6 40.8v8.6M214.6 40.8v8.6M233.7 40.8v8.6M262.3 40.8v8.6M281.3 40.8v8.6M300.4 40.8v8.6"/>
<path d="M319.4 40.8v8.6M343.2 40.8v8.6M362.3 40.8v8.6M381.3 40.8v8.6M393.3 54.9h-4.9l-1.3 1.2M393.3 51.1h-4.1v1.9l-4.1 4.2h-202.1l-.4 .4M393.3 49.8h-4.5v3l-3.8 3.9h-220.6l-.2 .2M393.3 48.6h-5v4l-3.6 3.6h-238.8l-.4 .3M393.3 47.3h-5.4v5.1l-3.3 3.3h-255.5l-.3 .3M393.3 46h-5.9v6.2l-2.9 3h-273.9l-.5 .4M393.3 44.8h-6.3v7.2l-2.7 2.7h-292.3l-.4 .4M393.3 43.5h-6.8v8.3l-2.3 2.4h-321.9l-.2 .2"/>
<path d="M393.3 42.2h-6.3l-.9 1v8.4l-2 2.1h-344.7M393.3 53.7h-3.7l-.4 .3M402.6 52.4h-3.8v4.4l2.4 2.4h5M402.6 51.1h-4.3v5.9l-3.7 3.8h-28l-1.4 1.4M402.6 49.8h-4.7v7l-3.5 3.5h-44.6l-.9 .9M402.6 48.6h-5.2v8l-3.2 3.3h-64l-.3 .3M402.6 47.3h-5.6v9.1l-3 3h-98.6l-.2 .3M402.6 46h-6.1v10.3l-2.7 2.7h-117.1l-.4 .3M402.6 44.8h-6.5v11.3l-2.5 2.4h-135.2l-.2 .3M402.6 43.5h-7v12.4l-2.2 2.2h-153.6l-.3 .2M402.6 42.2h-6.5l-.9 1v12.5l-1.9 1.9h-191.7l-.2 .3M402.6 53.7h-3.4v2.9l1.6 1.6h6.4"/>
<path d="M406.9 47.5h2.6l1.2 1.2v12.3l1.1 1.2h47l5.4 5.3v40.5l-1.9 1.9h-9.5l-9.6-9.6h-54.4l-2.7-2.7v-13.9l-3.2-3.2h-65.1l-.8 .8h-264.3M406.9 45h2.6l1.7 1.7v14.2l.8 .8h47l5.7 5.7v41.5l-10.6 10.5h-65.6l-4.8-4.8v-30.9l-2.4-2.4h-55.8l-2.4 2.4h-22.7l-4.8 4.7v7.2l-4.8 4.7h-233.3M406.9 50.1h2.7l.6 .6v10.5l1.5 1.5h47l5 5v12.2l-1.4 1.4h-75l-3.6-3.6v-13.1M406.9 42.4h3l1.8 1.8v16.5l.5 .6h47l6 5.9v41.8l-10.9 10.8h-7.3l-2.3 2.4v16l-.3 .2h-56.5l-6.6-6.6v-31.5h-54.8l-9.5 9.6v4.7l-4.7 4.8h-250.1M52.7 69.4v8.6M71.8 69.4v8.6M90.8 69.4v8.6M109.9 69.4v8.6M128.9 69.4v8.6M148 69.4v8.6M167 69.4v8.6M186.1 69.4v8.6"/>
<path d="M205.1 69.4v8.6M224.2 69.4v8.6M243.2 69.4v8.6M262.3 69.4v8.6M281.3 69.4v8.6M317 69.4v8.6M343.2 69.4v8.6M362.3 69.4v8.6M381.3 69.4v8.6M405.1 69.4v8.6M424.2 69.4v8.6M443.2 69.4v8.6"/>
<path d="M462.3 69.4v8.6M57.5 88.4v8.6M81.3 88.4v8.6M100.3 88.4v8.6M119.4 88.4v8.6M138.4 88.4v8.6M157.5 88.4v8.6M176.5 88.4v8.6M195.6 88.4v8.6M214.6 88.4v8.6M233.7 88.4v8.6M252.7 88.4v8.6"/>
<path d="M271.8 88.4v8.6M290.8 88.4v8.6M317 97.9v8.7M343.2 88.4v8.6M362.3 88.4v8.6M381.3 88.4v8.6M405.1 88.4v8.6M424.2 88.4v8.6M443.2 88.4v7.5l-1.1 1.1M462.3 97.9v8.7M62.2 107.5v8.6M86 107.5v8.6"/>
<path d="M105.1 107.5v8.6M124.1 107.5v8.6M143.2 107.5v8.6M162.2 107.5v8.6M181.3 107.5v8.6M200.3 107.5v8.6M219.4 107.5v8.6M238.4 107.5v8.6M257.5 107.5v8.6M276.5 107.5v8.6M295.6 107.5v9.3l.2 .2M405.1 107.5v8.6"/>
<path d="M424.2 107.5v8.6M443.2 107.5v8.6M57.5 126.5v8.6M76.5 126.5v8.6M95.6 126.5v8.6M114.6 126.5v8.6M133.7 126.5v8.6M152.7 126.5v8.6M171.8 126.5v8.6M190.8 126.5v8.6M209.9 126.5v8.6M228.9 126.5v8.6"/>
<path d="M248 126.5v8.6M267 126.5v8.6M295.8 120.3h19.8l1.4 1.5M309.9 126.5v8.6M362.3 126.5l-.1 7.7M405.1 126.5v8.6M424.2 126.5v8.6M443.2 126.5l-.1 7.1-1.5 1.5M462.3 136v8.7M55.1 145.6v8.6M78.9 145.6v8.6M102.7 145.6v8.6"/>
<path d="M174.1 145.6v8.6M245.6 145.6v8.6M269.4 145.6v8.6M293.2 145.6v8.6M317 145.6v8.6M321.8 152.7v4M343.2 145.6v8.6M362.3 145.6v8.6M381.3 145.6v8.6M421.8 145.6v8.6M443.2 145.6v8.6"/>
</g>
</svg>
